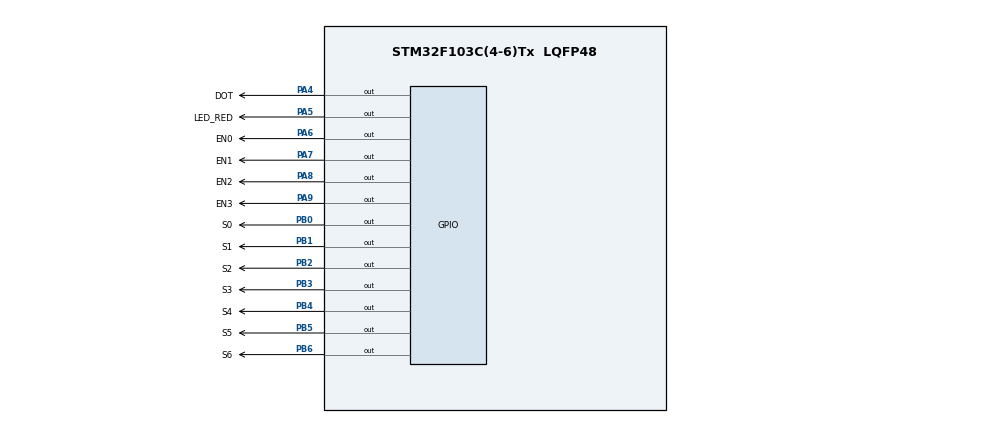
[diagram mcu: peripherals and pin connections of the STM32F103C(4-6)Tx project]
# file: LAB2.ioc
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Mcu.Family=STM32F1
Mcu.Name=STM32F103C(4-6)Tx
Mcu.Package=LQFP48
NVIC.PriorityGroup=NVIC_PRIORITYGROUP_4
NVIC.TIM2_IRQn=true\:0\:0\:false\:false\:true\:true\:true
PA4.GPIO_Label=DOT
PA4.Signal=GPIO_Output
PA5.GPIO_Label=LED_RED
PA5.Signal=GPIO_Output
PA6.GPIO_Label=EN0
PA6.Signal=GPIO_Output
PA7.GPIO_Label=EN1
PA7.Signal=GPIO_Output
PA8.GPIO_Label=EN2
PA8.Signal=GPIO_Output
PA9.GPIO_Label=EN3
PA9.Signal=GPIO_Output
PB0.GPIO_Label=S0
PB0.Signal=GPIO_Output
PB1.GPIO_Label=S1
PB1.Signal=GPIO_Output
PB2.GPIO_Label=S2
PB2.Signal=GPIO_Output
PB3.GPIO_Label=S3
PB3.Signal=GPIO_Output
PB4.GPIO_Label=S4
PB4.Signal=GPIO_Output
PB5.GPIO_Label=S5
PB5.Signal=GPIO_Output
PB6.GPIO_Label=S6
PB6.Signal=GPIO_Output
ProjectManager.HeapSize=0x200
ProjectManager.StackSize=0x400
ProjectManager.TargetToolchain=STM32CubeIDE
RCC.APB1Freq_Value=8000000
RCC.APB2Freq_Value=8000000
TIM2.Period=9
TIM2.Prescaler=7999
VP_SYS_VS_ND.Mode=No_Debug
VP_TIM2_VS_ClockSourceINT.Mode=Internal
board=custom

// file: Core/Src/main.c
/* USER CODE BEGIN Header */
/**
  ******************************************************************************
  * @file           : main.c
  * @brief          : Main program body
  ******************************************************************************
  * @attention
  *
  * <h2><center>&copy; Copyright (c) 2024 STMicroelectronics.
  * All rights reserved.</center></h2>
  *
  * This software component is licensed by ST under BSD 3-Clause license,
  * the "License"; You may not use this file except in compliance with the
  * License. You may obtain a copy of the License at:
  *                        opensource.org/licenses/BSD-3-Clause
  *
  ******************************************************************************
  */
/* USER CODE END Header */
#include "main.h"

/* USER CODE BEGIN Includes */
#include "software_timer.h"
/* USER CODE END Includes */

TIM_HandleTypeDef htim2;

void SystemClock_Config(void);
static void MX_GPIO_Init(void);
static void MX_TIM2_Init(void);

/* USER CODE BEGIN 0 */
void  display7SEG(int num){
	int SMap[10] = {
	        0b00111111, // 0
	        0b00000110, // 1
	        0b01011011, // 2
	        0b01001111, // 3
	        0b01100110, // 4
	        0b01101101, // 5
	        0b01111101, // 6
	        0b00000111, // 7
	        0b01111111, // 8
	        0b01101111  // 9
	    };
	    if (num < 0 || num > 9) {
	        return;
	    }
	    int segments = SMap[num];
	    HAL_GPIO_WritePin(S0_GPIO_Port, S0_Pin, (segments & 0b00000001) ? GPIO_PIN_RESET : GPIO_PIN_SET);
	    HAL_GPIO_WritePin(S1_GPIO_Port, S1_Pin, (segments & 0b00000010) ? GPIO_PIN_RESET : GPIO_PIN_SET);
	    HAL_GPIO_WritePin(S2_GPIO_Port, S2_Pin, (segments & 0b00000100) ? GPIO_PIN_RESET : GPIO_PIN_SET);
	    HAL_GPIO_WritePin(S3_GPIO_Port, S3_Pin, (segments & 0b00001000) ? GPIO_PIN_RESET : GPIO_PIN_SET);
	    HAL_GPIO_WritePin(S4_GPIO_Port, S4_Pin, (segments & 0b00010000) ? GPIO_PIN_RESET : GPIO_PIN_SET);
	    HAL_GPIO_WritePin(S5_GPIO_Port, S5_Pin, (segments & 0b00100000) ? GPIO_PIN_RESET : GPIO_PIN_SET);
	    HAL_GPIO_WritePin(S6_GPIO_Port, S6_Pin, (segments & 0b01000000) ? GPIO_PIN_RESET : GPIO_PIN_SET);
	}
const int MAX_LED = 4;
 int index_led = 0;
 void update7SEG (int index, int num) {
      switch ( index ) {
        case 0:
          // Display the first 7 SEG with led_buffer [0]
     	   HAL_GPIO_WritePin ( EN1_GPIO_Port , EN1_Pin, GPIO_PIN_SET);
     	   HAL_GPIO_WritePin ( EN2_GPIO_Port , EN2_Pin, GPIO_PIN_SET);
     	   HAL_GPIO_WritePin ( EN3_GPIO_Port , EN3_Pin, GPIO_PIN_SET);
     	   display7SEG(num);
     	   HAL_GPIO_WritePin ( EN0_GPIO_Port , EN0_Pin, GPIO_PIN_RESET);
          break ;
        case 1:
          // Display the second 7 SEG with led_buffer [1]
     	   HAL_GPIO_WritePin ( EN0_GPIO_Port , EN0_Pin, GPIO_PIN_SET);
     	   HAL_GPIO_WritePin ( EN2_GPIO_Port , EN2_Pin, GPIO_PIN_SET);
     	   HAL_GPIO_WritePin ( EN3_GPIO_Port , EN3_Pin, GPIO_PIN_SET);
       	   display7SEG(num);
        	   HAL_GPIO_WritePin ( EN1_GPIO_Port , EN1_Pin, GPIO_PIN_RESET);
          break ;
        case 2:
          // Display the third 7 SEG with led_buffer [2]
     	   HAL_GPIO_WritePin ( EN1_GPIO_Port , EN1_Pin, GPIO_PIN_SET);
        	   HAL_GPIO_WritePin ( EN0_GPIO_Port , EN0_Pin, GPIO_PIN_SET);
        	   HAL_GPIO_WritePin ( EN3_GPIO_Port , EN3_Pin, GPIO_PIN_SET);
        	   display7SEG(num);
        	   HAL_GPIO_WritePin ( EN2_GPIO_Port , EN2_Pin, GPIO_PIN_RESET);
          break ;
        case 3:
          // Display the forth 7 SEG with led_buffer [3]
     	   HAL_GPIO_WritePin ( EN1_GPIO_Port , EN1_Pin, GPIO_PIN_SET);
        	   HAL_GPIO_WritePin ( EN2_GPIO_Port , EN2_Pin, GPIO_PIN_SET);
        	   HAL_GPIO_WritePin ( EN0_GPIO_Port , EN0_Pin, GPIO_PIN_SET);
        	   display7SEG(num);
        	   HAL_GPIO_WritePin ( EN3_GPIO_Port , EN3_Pin, GPIO_PIN_RESET);
          break ;
        default :
          break ;
       }
  }
 int counter = 200;
 int cnt = 100;
/* USER CODE END 0 */

int main(void)
{

  /* MCU Configuration--------------------------------------------------------*/

  /* Reset of all peripherals, Initializes the Flash interface and the Systick. */
  HAL_Init();

  /* USER CODE BEGIN Init */
  MX_GPIO_Init () ;
  MX_TIM2_Init () ;
  /* USER CODE END Init */

  /* Configure the system clock */
  SystemClock_Config();

  /* Initialize all configured peripherals */
  MX_GPIO_Init();
  MX_TIM2_Init();
  /* USER CODE BEGIN 2 */
  HAL_TIM_Base_Start_IT (& htim2 ) ;

  /* USER CODE END 2 */

  /* Infinite loop */
  /* USER CODE BEGIN WHILE */
  int hour = 15 , minute = 8 , second = 50;
  setTimer1(100);
  setTimer2(50);
  void updateClockBuffer (){
	  if(timer1_flag == 1){
		  setTimer1(100);
		  HAL_GPIO_TogglePin(DOT_GPIO_Port, DOT_Pin);
		  index_led++;
		  if(index_led > 3){
			  index_led = 0;
		  }
	  }
	  switch (index_led){
	  case 0:
		  if(hour<10){
			  update7SEG (0, 0);
		  }
		  if(hour>=10){
			  update7SEG (0, hour/10);
		  }
		  break;
	  case 1:
		  update7SEG (1, hour%10);
		  break;
	  case 2:
		  if(minute<10){
			  update7SEG (2, 0);
		  }
		  if(minute>=10){
			  update7SEG (2, minute/10);
		  }
		  break;
	  case 3:
		  update7SEG (3, minute%10);
	      break;
	  default:
	      break;
	  }
   }
  while (1)
  {
	  if(timer2_flag == 1){
		  setTimer2(50);
	      second ++;
	  }
	  if ( second >= 60) {
		  second = 0;
	      minute ++;
	  }
	  if( minute >= 60) {
	      minute = 0;
	      hour ++;
	  }
	  if( hour >=24) {
	      hour = 0;
	  }
	  updateClockBuffer ();
    /* USER CODE END WHILE */

  }
}

void SystemClock_Config(void)
{
  RCC_OscInitTypeDef RCC_OscInitStruct = {0};
  RCC_ClkInitTypeDef RCC_ClkInitStruct = {0};

  /** Initializes the RCC Oscillators according to the specified parameters
  * in the RCC_OscInitTypeDef structure.
  */
  RCC_OscInitStruct.OscillatorType = RCC_OSCILLATORTYPE_HSI;
  RCC_OscInitStruct.HSIState = RCC_HSI_ON;
  RCC_OscInitStruct.HSICalibrationValue = RCC_HSICALIBRATION_DEFAULT;
  RCC_OscInitStruct.PLL.PLLState = RCC_PLL_NONE;
  if (HAL_RCC_OscConfig(&RCC_OscInitStruct) != HAL_OK)
  {
    Error_Handler();
  }
  /** Initializes the CPU, AHB and APB buses clocks
  */
  RCC_ClkInitStruct.ClockType = RCC_CLOCKTYPE_HCLK|RCC_CLOCKTYPE_SYSCLK
                              |RCC_CLOCKTYPE_PCLK1|RCC_CLOCKTYPE_PCLK2;
  RCC_ClkInitStruct.SYSCLKSource = RCC_SYSCLKSOURCE_HSI;
  RCC_ClkInitStruct.AHBCLKDivider = RCC_SYSCLK_DIV1;
  RCC_ClkInitStruct.APB1CLKDivider = RCC_HCLK_DIV1;
  RCC_ClkInitStruct.APB2CLKDivider = RCC_HCLK_DIV1;

  if (HAL_RCC_ClockConfig(&RCC_ClkInitStruct, FLASH_LATENCY_0) != HAL_OK)
  {
    Error_Handler();
  }
}

static void MX_TIM2_Init(void)
{

  TIM_ClockConfigTypeDef sClockSourceConfig = {0};
  TIM_MasterConfigTypeDef sMasterConfig = {0};

  htim2.Instance = TIM2;
  htim2.Init.Prescaler = 7999;
  htim2.Init.CounterMode = TIM_COUNTERMODE_UP;
  htim2.Init.Period = 9;
  htim2.Init.ClockDivision = TIM_CLOCKDIVISION_DIV1;
  htim2.Init.AutoReloadPreload = TIM_AUTORELOAD_PRELOAD_DISABLE;
  if (HAL_TIM_Base_Init(&htim2) != HAL_OK)
  {
    Error_Handler();
  }
  sClockSourceConfig.ClockSource = TIM_CLOCKSOURCE_INTERNAL;
  if (HAL_TIM_ConfigClockSource(&htim2, &sClockSourceConfig) != HAL_OK)
  {
    Error_Handler();
  }
  sMasterConfig.MasterOutputTrigger = TIM_TRGO_RESET;
  sMasterConfig.MasterSlaveMode = TIM_MASTERSLAVEMODE_DISABLE;
  if (HAL_TIMEx_MasterConfigSynchronization(&htim2, &sMasterConfig) != HAL_OK)
  {
    Error_Handler();
  }

}

static void MX_GPIO_Init(void)
{
  GPIO_InitTypeDef GPIO_InitStruct = {0};

  /* GPIO Ports Clock Enable */
  __HAL_RCC_GPIOA_CLK_ENABLE();
  __HAL_RCC_GPIOB_CLK_ENABLE();

  /*Configure GPIO pin Output Level */
  HAL_GPIO_WritePin(GPIOA, GPIO_PIN_1|ENM0_Pin|ENM1_Pin|DOT_Pin
                          |LED_RED_Pin|EN0_Pin|EN1_Pin|EN2_Pin
                          |EN3_Pin|ENM2_Pin|ENM3_Pin|ENM4_Pin
                          |ENM5_Pin|ENM6_Pin|ENM7_Pin, GPIO_PIN_RESET);

  /*Configure GPIO pin Output Level */
  HAL_GPIO_WritePin(GPIOB, S0_Pin|S1_Pin|S2_Pin|S3_Pin
                          |S4_Pin|S5_Pin|S6_Pin, GPIO_PIN_RESET);

  /*Configure GPIO pins : PA1 ENM0_Pin ENM1_Pin DOT_Pin
                           LED_RED_Pin EN0_Pin EN1_Pin EN2_Pin
                           EN3_Pin ENM2_Pin ENM3_Pin ENM4_Pin
                           ENM5_Pin ENM6_Pin ENM7_Pin */
  GPIO_InitStruct.Pin = GPIO_PIN_1|ENM0_Pin|ENM1_Pin|DOT_Pin
                          |LED_RED_Pin|EN0_Pin|EN1_Pin|EN2_Pin
                          |EN3_Pin|ENM2_Pin|ENM3_Pin|ENM4_Pin
                          |ENM5_Pin|ENM6_Pin|ENM7_Pin;
  GPIO_InitStruct.Mode = GPIO_MODE_OUTPUT_PP;
  GPIO_InitStruct.Pull = GPIO_NOPULL;
  GPIO_InitStruct.Speed = GPIO_SPEED_FREQ_LOW;
  HAL_GPIO_Init(GPIOA, &GPIO_InitStruct);

  /*Configure GPIO pins : S0_Pin S1_Pin S2_Pin S3_Pin
                           S4_Pin S5_Pin S6_Pin */
  GPIO_InitStruct.Pin = S0_Pin|S1_Pin|S2_Pin|S3_Pin
                          |S4_Pin|S5_Pin|S6_Pin;
  GPIO_InitStruct.Mode = GPIO_MODE_OUTPUT_PP;
  GPIO_InitStruct.Pull = GPIO_NOPULL;
  GPIO_InitStruct.Speed = GPIO_SPEED_FREQ_LOW;
  HAL_GPIO_Init(GPIOB, &GPIO_InitStruct);

}

/* USER CODE BEGIN 4 */
void HAL_TIM_PeriodElapsedCallback ( TIM_HandleTypeDef * htim )
 {
   timerRun();
}
/* USER CODE END 4 */

void Error_Handler(void)
{
  __disable_irq();
  while (1)
  {
  }
}

/************************ (C) COPYRIGHT STMicroelectronics *****END OF FILE****/
